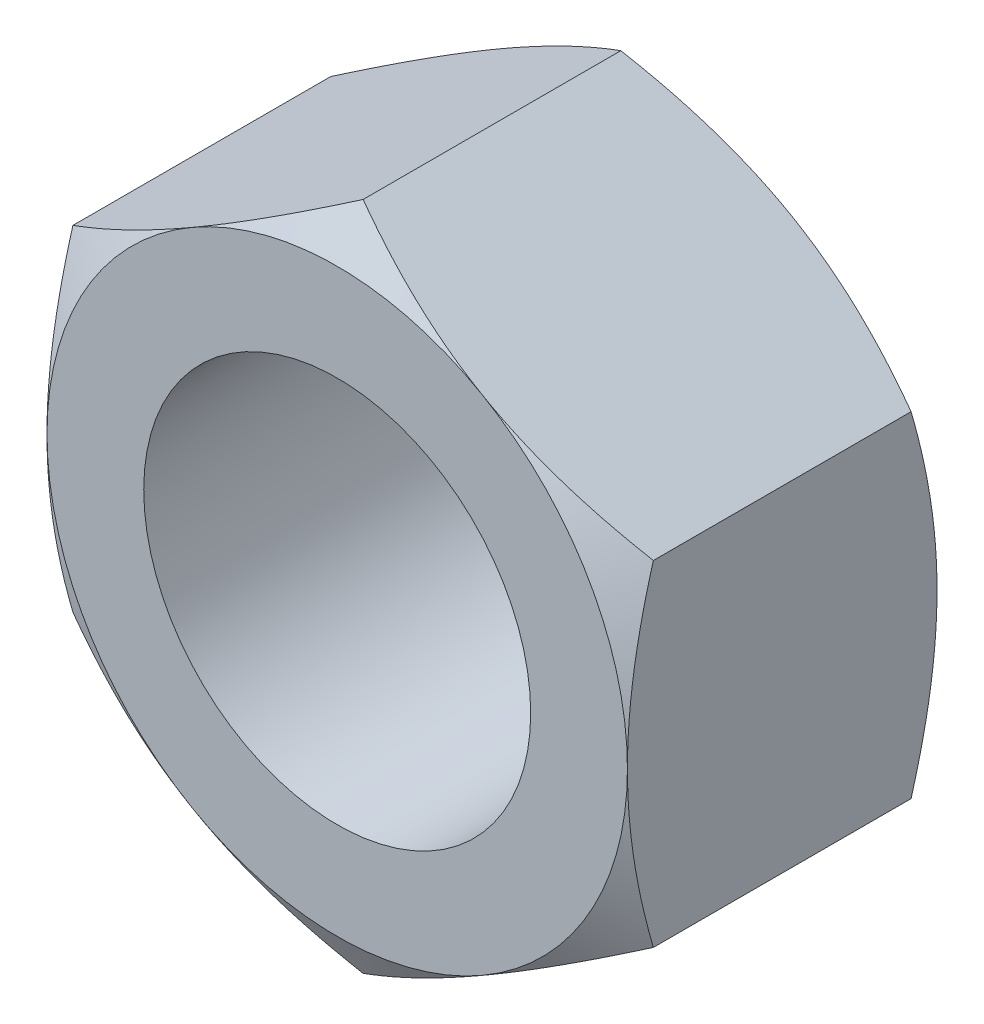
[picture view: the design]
ISO-10303-21;
HEADER;
FILE_DESCRIPTION(('STEP AP214'),'2;1');
FILE_NAME('part.step','',(''),(''),'','','');
FILE_SCHEMA(('AUTOMOTIVE_DESIGN { 1 0 10303 214 1 1 1 1 }'));
ENDSEC;
DATA;
#1=APPLICATION_CONTEXT('core data for automotive mechanical design processes');
#2=APPLICATION_PROTOCOL_DEFINITION('international standard','automotive_design',2000,#1);
#3=PRODUCT_CONTEXT('',#1,'mechanical');
#4=PRODUCT('Part','Part','',(#3));
#5=PRODUCT_RELATED_PRODUCT_CATEGORY('part','',(#4));
#6=PRODUCT_DEFINITION_FORMATION('','',#4);
#7=PRODUCT_DEFINITION_CONTEXT('part definition',#1,'design');
#8=PRODUCT_DEFINITION('design','',#6,#7);
#9=PRODUCT_DEFINITION_SHAPE('','',#8);
#10=(LENGTH_UNIT() NAMED_UNIT(*) SI_UNIT(.MILLI.,.METRE.));
#11=(NAMED_UNIT(*) PLANE_ANGLE_UNIT() SI_UNIT($,.RADIAN.));
#12=(NAMED_UNIT(*) SI_UNIT($,.STERADIAN.) SOLID_ANGLE_UNIT());
#13=UNCERTAINTY_MEASURE_WITH_UNIT(LENGTH_MEASURE(1.E-05),#10,'distance_accuracy_value','');
#14=(GEOMETRIC_REPRESENTATION_CONTEXT(3) GLOBAL_UNCERTAINTY_ASSIGNED_CONTEXT((#13)) GLOBAL_UNIT_ASSIGNED_CONTEXT((#10,
#11,#12)) REPRESENTATION_CONTEXT('',''));
#15=CARTESIAN_POINT('',(0.,0.,0.));
#16=DIRECTION('',(0.,0.,1.));
#17=DIRECTION('',(1.,0.,0.));
#18=AXIS2_PLACEMENT_3D('',#15,#16,#17);
#19=CARTESIAN_POINT('',(-15.,25.9807621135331,0.));
#20=DIRECTION('',(0.,0.,-1.));
#21=DIRECTION('',(-1.,0.,0.));
#22=AXIS2_PLACEMENT_3D('',#19,#20,#21);
#23=PLANE('',#22);
#24=CARTESIAN_POINT('',(0.,0.,0.));
#25=DIRECTION('',(0.,0.,1.));
#26=DIRECTION('',(1.,0.,0.));
#27=AXIS2_PLACEMENT_3D('',#24,#25,#26);
#28=CIRCLE('',#27,10.);
#29=CARTESIAN_POINT('',(10.,0.,0.));
#30=VERTEX_POINT('',#29);
#31=EDGE_CURVE('E319',#30,#30,#28,.T.);
#32=ORIENTED_EDGE('',*,*,#31,.F.);
#33=EDGE_LOOP('',(#32));
#34=FACE_BOUND('',#33,.T.);
#35=CARTESIAN_POINT('',(0.,0.,0.));
#36=DIRECTION('',(0.,0.,-1.));
#37=DIRECTION('',(-1.,0.,0.));
#38=AXIS2_PLACEMENT_3D('',#35,#36,#37);
#39=CIRCLE('',#38,15.);
#40=CARTESIAN_POINT('',(-14.9999999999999,0.,0.));
#41=VERTEX_POINT('',#40);
#42=CARTESIAN_POINT('',(-7.5000000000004,12.9903810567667,0.));
#43=VERTEX_POINT('',#42);
#44=EDGE_CURVE('E327',#41,#43,#39,.T.);
#45=ORIENTED_EDGE('',*,*,#44,.F.);
#46=CARTESIAN_POINT('',(0.,0.,0.));
#47=DIRECTION('',(0.,0.,-1.));
#48=DIRECTION('',(-1.,0.,0.));
#49=AXIS2_PLACEMENT_3D('',#46,#47,#48);
#50=CIRCLE('',#49,15.);
#51=CARTESIAN_POINT('',(-7.50000000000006,-12.9903810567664,0.));
#52=VERTEX_POINT('',#51);
#53=EDGE_CURVE('E149',#41,#52,#50,.F.);
#54=ORIENTED_EDGE('',*,*,#53,.T.);
#55=CARTESIAN_POINT('',(7.49999999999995,-12.9903810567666,0.));
#56=VERTEX_POINT('',#55);
#57=EDGE_CURVE('E251',#52,#56,#50,.F.);
#58=ORIENTED_EDGE('',*,*,#57,.T.);
#59=CARTESIAN_POINT('',(14.9999999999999,-2.22044604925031E-13,0.));
#60=VERTEX_POINT('',#59);
#61=EDGE_CURVE('E152',#56,#60,#50,.F.);
#62=ORIENTED_EDGE('',*,*,#61,.T.);
#63=CARTESIAN_POINT('',(7.50000000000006,12.9903810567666,0.));
#64=VERTEX_POINT('',#63);
#65=EDGE_CURVE('E127',#60,#64,#50,.F.);
#66=ORIENTED_EDGE('',*,*,#65,.T.);
#67=EDGE_CURVE('E140',#64,#43,#50,.F.);
#68=ORIENTED_EDGE('',*,*,#67,.T.);
#69=EDGE_LOOP('',(#45,#54,#58,#62,#66,#68));
#70=FACE_BOUND('',#69,.T.);
#71=ADVANCED_FACE('F32',(#34,#70),#23,.F.);
#72=CARTESIAN_POINT('',(0.,0.,0.));
#73=DIRECTION('',(0.,0.,-1.));
#74=DIRECTION('',(-1.,0.,0.));
#75=AXIS2_PLACEMENT_3D('',#72,#73,#74);
#76=CONICAL_SURFACE('',#75,15.,1.0471975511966);
#77=CARTESIAN_POINT('',(-15.0000000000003,-23.3393093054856,-7.35768755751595));
#78=CARTESIAN_POINT('',(-15.0000000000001,-23.0113763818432,-7.19841663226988));
#79=CARTESIAN_POINT('',(-15.0000000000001,-22.6830606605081,-7.03993424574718));
#80=CARTESIAN_POINT('',(-15.,-22.0255837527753,-6.724725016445));
#81=CARTESIAN_POINT('',(-15.,-21.6964225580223,-6.56799819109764));
#82=CARTESIAN_POINT('',(-15.0000000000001,-20.7074642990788,-6.10067791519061));
#83=CARTESIAN_POINT('',(-15.,-20.0462884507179,-5.79299136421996));
#84=CARTESIAN_POINT('',(-15.,-18.7159764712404,-5.18557696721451));
#85=CARTESIAN_POINT('',(-15.,-18.0468166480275,-4.88590088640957));
#86=CARTESIAN_POINT('',(-15.,-16.7032011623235,-4.29870839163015));
#87=CARTESIAN_POINT('',(-15.,-16.0287457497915,-4.01119140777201));
#88=CARTESIAN_POINT('',(-15.,-14.6515945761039,-3.44250105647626));
#89=CARTESIAN_POINT('',(-15.,-13.9486896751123,-3.16183152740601));
#90=CARTESIAN_POINT('',(-15.,-12.5346804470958,-2.62154818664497));
#91=CARTESIAN_POINT('',(-15.,-11.823575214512,-2.36193672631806));
#92=CARTESIAN_POINT('',(-15.,-10.3933623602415,-1.87053112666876));
#93=CARTESIAN_POINT('',(-15.,-9.67427399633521,-1.63868138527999));
#94=CARTESIAN_POINT('',(-15.,-8.22571576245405,-1.21017371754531));
#95=CARTESIAN_POINT('',(-15.,-7.4962492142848,-1.01350479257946));
#96=CARTESIAN_POINT('',(-15.,-6.39610270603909,-0.752490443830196));
#97=CARTESIAN_POINT('',(-15.,-6.02939002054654,-0.671323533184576));
#98=CARTESIAN_POINT('',(-15.,-5.29344467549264,-0.521286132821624));
#99=CARTESIAN_POINT('',(-15.,-4.92421206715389,-0.452415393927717));
#100=CARTESIAN_POINT('',(-15.,-4.18347621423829,-0.328181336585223));
#101=CARTESIAN_POINT('',(-15.,-3.81197300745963,-0.272817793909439));
#102=CARTESIAN_POINT('',(-15.,-3.06708460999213,-0.176699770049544));
#103=CARTESIAN_POINT('',(-15.,-2.69369950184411,-0.135944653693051));
#104=CARTESIAN_POINT('',(-15.,-1.95047864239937,-0.0703683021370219));
#105=CARTESIAN_POINT('',(-15.,-1.58066088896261,-0.0453443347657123));
#106=CARTESIAN_POINT('',(-15.,-0.840299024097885,-0.0109620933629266));
#107=CARTESIAN_POINT('',(-15.0000000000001,-0.469754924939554,-0.00160355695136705));
#108=CARTESIAN_POINT('',(-15.,0.271400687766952,0.0012249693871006));
#109=CARTESIAN_POINT('',(-15.,0.642012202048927,-0.00530522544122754));
#110=CARTESIAN_POINT('',(-15.0000000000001,1.38262798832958,-0.0340942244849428));
#111=CARTESIAN_POINT('',(-15.0000000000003,1.75263223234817,-0.0563537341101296));
#112=CARTESIAN_POINT('',(-15.0000000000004,2.63937167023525,-0.128074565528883));
#113=CARTESIAN_POINT('',(-15.0000000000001,3.15552506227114,-0.18485970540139));
#114=CARTESIAN_POINT('',(-14.9999999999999,4.18405620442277,-0.325966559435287));
#115=CARTESIAN_POINT('',(-15.,4.69643344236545,-0.41029194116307));
#116=CARTESIAN_POINT('',(-15.0000000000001,5.71689756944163,-0.603479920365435));
#117=CARTESIAN_POINT('',(-15.,6.22498092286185,-0.712361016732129));
#118=CARTESIAN_POINT('',(-15.,7.23607939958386,-0.951336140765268));
#119=CARTESIAN_POINT('',(-15.,7.73909459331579,-1.08142987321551));
#120=CARTESIAN_POINT('',(-15.,8.75152378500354,-1.36284884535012));
#121=CARTESIAN_POINT('',(-15.,9.26082088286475,-1.51459173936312));
#122=CARTESIAN_POINT('',(-15.,10.27439709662,-1.83391678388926));
#123=CARTESIAN_POINT('',(-15.,10.7786761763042,-2.00149904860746));
#124=CARTESIAN_POINT('',(-15.,11.7824677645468,-2.34982725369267));
#125=CARTESIAN_POINT('',(-15.,12.2819817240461,-2.53056903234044));
#126=CARTESIAN_POINT('',(-15.,13.276854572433,-2.90307352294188));
#127=CARTESIAN_POINT('',(-15.,13.7722135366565,-3.09483603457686));
#128=CARTESIAN_POINT('',(-15.,15.0436675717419,-3.60070607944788));
#129=CARTESIAN_POINT('',(-15.,15.817045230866,-3.92163726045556));
#130=CARTESIAN_POINT('',(-15.,17.3564052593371,-4.5808277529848));
#131=CARTESIAN_POINT('',(-15.,18.1223869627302,-4.91908860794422));
#132=CARTESIAN_POINT('',(-15.,19.6485392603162,-5.60905898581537));
#133=CARTESIAN_POINT('',(-15.,20.4087079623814,-5.9607726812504));
#134=CARTESIAN_POINT('',(-15.,21.9240967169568,-6.67461099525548));
#135=CARTESIAN_POINT('',(-15.,22.6793169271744,-7.03673528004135));
#136=CARTESIAN_POINT('',(-15.,24.1867764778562,-7.76974794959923));
#137=CARTESIAN_POINT('',(-15.,24.9390102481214,-8.14064776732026));
#138=CARTESIAN_POINT('',(-15.,26.4401635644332,-8.88909646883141));
#139=CARTESIAN_POINT('',(-15.,27.1890830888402,-9.26664539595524));
#140=CARTESIAN_POINT('',(-15.,28.6840389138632,-10.027077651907));
#141=CARTESIAN_POINT('',(-15.,29.4300757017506,-10.4099600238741));
#142=CARTESIAN_POINT('',(-15.,30.9198465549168,-11.1801693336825));
#143=CARTESIAN_POINT('',(-15.,31.6635806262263,-11.5674962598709));
#144=CARTESIAN_POINT('',(-15.,33.7472761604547,-12.6592216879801));
#145=CARTESIAN_POINT('',(-15.,35.0850614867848,-13.3677730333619));
#146=CARTESIAN_POINT('',(-15.,37.756014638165,-14.7936653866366));
#147=CARTESIAN_POINT('',(-15.,39.0891822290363,-15.5110068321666));
#148=CARTESIAN_POINT('',(-15.,41.7479806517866,-16.9501647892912));
#149=CARTESIAN_POINT('',(-15.,43.0736221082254,-17.6719616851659));
#150=CARTESIAN_POINT('',(-15.,45.0599534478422,-18.7584424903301));
#151=CARTESIAN_POINT('',(-15.,45.7216867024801,-19.1212214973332));
#152=CARTESIAN_POINT('',(-15.,47.0445303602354,-19.8479113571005));
#153=CARTESIAN_POINT('',(-15.0000000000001,47.7056407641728,-20.211822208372));
#154=CARTESIAN_POINT('',(-15.0000000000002,48.366476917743,-20.5762305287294));
#155=B_SPLINE_CURVE_WITH_KNOTS('',3,(#77,#78,#79,#80,#81,#82,#83,#84,#85,#86,#87,#88,#89,#90,
#91,#92,#93,#94,#95,#96,#97,#98,#99,#100,#101,#102,#103,#104,#105,#106,#107,#108,#109,#110,#111,
#112,#113,#114,#115,#116,#117,#118,#119,#120,#121,#122,#123,#124,#125,#126,#127,#128,#129,#130,
#131,#132,#133,#134,#135,#136,#137,#138,#139,#140,#141,#142,#143,#144,#145,#146,#147,#148,#149,
#150,#151,#152,#153,#154),.UNSPECIFIED.,.F.,.F.,(4,2,2,2,2,2,2,2,2,2,2,2,2,2,2,2,2,2,2,2,2,2,2,
2,2,2,2,2,2,2,2,2,2,2,2,2,2,2,4),(0.,1.09369135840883,2.1873935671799,4.37511793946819,
6.57462034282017,8.77401954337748,11.0443689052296,13.3149714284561,15.5809474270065,
17.8462137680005,18.9728046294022,20.099372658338,21.2259219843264,22.3524223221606,
23.4640902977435,24.5757396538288,25.6874019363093,26.799114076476,28.3560578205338,
29.9132089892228,31.4715371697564,33.0298436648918,34.6238022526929,36.2177723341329,
37.8112404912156,39.4046796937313,41.9163419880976,44.4282283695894,46.9409002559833,
49.4534916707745,51.9695595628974,54.4856438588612,57.0012824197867,59.5169143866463,
64.0583868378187,68.6000863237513,73.1282984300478,75.3922533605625,77.6562053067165),.UNSPECIFIED.);
#156=CARTESIAN_POINT('',(-15.,8.66025403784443,-1.33974596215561));
#157=VERTEX_POINT('',#156);
#158=EDGE_CURVE('E157',#157,#41,#155,.F.);
#159=ORIENTED_EDGE('',*,*,#158,.T.);
#160=ORIENTED_EDGE('',*,*,#44,.T.);
#161=CARTESIAN_POINT('',(0.000200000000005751,17.3206235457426,-1.3398126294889));
#162=CARTESIAN_POINT('',(-0.329494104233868,17.1302745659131,-1.22992178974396));
#163=CARTESIAN_POINT('',(-0.660474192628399,16.9391831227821,-1.12501758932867));
#164=CARTESIAN_POINT('',(-1.32508844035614,16.5554679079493,-0.92656858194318));
#165=CARTESIAN_POINT('',(-1.65872343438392,16.3628436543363,-0.833027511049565));
#166=CARTESIAN_POINT('',(-2.32929228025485,15.9756905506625,-0.658562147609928));
#167=CARTESIAN_POINT('',(-2.66623200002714,15.7811583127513,-0.577667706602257));
#168=CARTESIAN_POINT('',(-3.34245276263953,15.3907420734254,-0.430232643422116));
#169=CARTESIAN_POINT('',(-3.68173367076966,15.1948581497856,-0.363691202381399));
#170=CARTESIAN_POINT('',(-4.35394314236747,14.8067578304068,-0.247792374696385));
#171=CARTESIAN_POINT('',(-4.6868218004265,14.6145702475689,-0.198051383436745));
#172=CARTESIAN_POINT('',(-5.35410443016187,14.2293144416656,-0.114646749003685));
#173=CARTESIAN_POINT('',(-5.68850843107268,14.0362462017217,-0.0809834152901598));
#174=CARTESIAN_POINT('',(-6.35787818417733,13.6497853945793,-0.0305840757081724));
#175=CARTESIAN_POINT('',(-6.6928427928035,13.4563934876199,-0.013827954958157));
#176=CARTESIAN_POINT('',(-7.36308121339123,13.0694311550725,0.0023966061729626));
#177=CARTESIAN_POINT('',(-7.69835501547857,12.8758607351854,0.00186558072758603));
#178=CARTESIAN_POINT('',(-8.32514688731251,12.5139822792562,-0.0152766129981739));
#179=CARTESIAN_POINT('',(-8.61670962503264,12.3456484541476,-0.0297968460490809));
#180=CARTESIAN_POINT('',(-9.19916443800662,12.0093680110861,-0.0716371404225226));
#181=CARTESIAN_POINT('',(-9.49005646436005,11.8414214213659,-0.0989581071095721));
#182=CARTESIAN_POINT('',(-10.0710118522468,11.5060066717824,-0.165923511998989));
#183=CARTESIAN_POINT('',(-10.3610743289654,11.3385390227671,-0.20557812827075));
#184=CARTESIAN_POINT('',(-10.9398394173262,11.0043888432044,-0.296515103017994));
#185=CARTESIAN_POINT('',(-11.2285419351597,10.8377063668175,-0.347798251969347));
#186=CARTESIAN_POINT('',(-12.1049144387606,10.3317324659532,-0.520386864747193));
#187=CARTESIAN_POINT('',(-12.6900465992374,9.99390625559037,-0.658901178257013));
#188=CARTESIAN_POINT('',(-13.8515859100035,9.32329122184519,-0.973271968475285));
#189=CARTESIAN_POINT('',(-14.4280079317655,8.99049381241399,-1.14905461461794));
#190=CARTESIAN_POINT('',(-15.0002,8.66013856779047,-1.33981262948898));
#191=B_SPLINE_CURVE_WITH_KNOTS('',3,(#161,#162,#163,#164,#165,#166,#167,#168,#169,#170,#171,
#172,#173,#174,#175,#176,#177,#178,#179,#180,#181,#182,#183,#184,#185,#186,#187,#188,#189,#190),
.UNSPECIFIED.,.F.,.F.,(4,2,2,2,2,2,2,2,2,2,2,2,2,2,4),(0.,1.18875411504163,2.37789802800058,
3.56980778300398,4.76164951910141,5.92407379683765,7.0865204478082,8.24758247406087,
9.40860862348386,10.4193068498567,11.4300765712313,12.4416826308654,13.4533574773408,
15.5211962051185,17.5849760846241),.UNSPECIFIED.);
#192=EDGE_CURVE('E189',#43,#157,#191,.T.);
#193=ORIENTED_EDGE('',*,*,#192,.T.);
#194=EDGE_LOOP('',(#159,#160,#193));
#195=FACE_BOUND('',#194,.T.);
#196=ADVANCED_FACE('F176',(#195),#76,.T.);
#197=CARTESIAN_POINT('',(15.0001999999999,8.66013856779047,-1.3398126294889));
#198=CARTESIAN_POINT('',(14.6705058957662,8.85048754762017,-1.22992178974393));
#199=CARTESIAN_POINT('',(14.3395258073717,9.04157899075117,-1.12501758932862));
#200=CARTESIAN_POINT('',(13.674911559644,9.42529420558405,-0.926568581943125));
#201=CARTESIAN_POINT('',(13.3412765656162,9.61791845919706,-0.833027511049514));
#202=CARTESIAN_POINT('',(12.6707077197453,10.0050715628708,-0.658562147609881));
#203=CARTESIAN_POINT('',(12.333767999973,10.199603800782,-0.577667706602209));
#204=CARTESIAN_POINT('',(11.6575472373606,10.5900200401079,-0.430232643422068));
#205=CARTESIAN_POINT('',(11.3182663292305,10.7859039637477,-0.363691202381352));
#206=CARTESIAN_POINT('',(10.6460568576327,11.1740042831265,-0.247792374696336));
#207=CARTESIAN_POINT('',(10.3131781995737,11.3661918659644,-0.198051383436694));
#208=CARTESIAN_POINT('',(9.6458955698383,11.7514476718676,-0.114646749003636));
#209=CARTESIAN_POINT('',(9.3114915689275,11.9445159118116,-0.0809834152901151));
#210=CARTESIAN_POINT('',(8.64212181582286,12.3309767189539,-0.0305840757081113));
#211=CARTESIAN_POINT('',(8.30715720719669,12.5243686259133,-0.0138279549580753));
#212=CARTESIAN_POINT('',(7.63691878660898,12.9113309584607,0.0023966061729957));
#213=CARTESIAN_POINT('',(7.30164498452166,13.1049013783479,0.00186558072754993));
#214=CARTESIAN_POINT('',(6.67485311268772,13.4667798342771,-0.0152766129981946));
#215=CARTESIAN_POINT('',(6.38329037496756,13.6351136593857,-0.0297968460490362));
#216=CARTESIAN_POINT('',(5.80083556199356,13.9713941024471,-0.0716371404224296));
#217=CARTESIAN_POINT('',(5.50994353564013,14.1393406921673,-0.0989581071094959));
#218=CARTESIAN_POINT('',(4.92898814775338,14.4747554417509,-0.165923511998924));
#219=CARTESIAN_POINT('',(4.63892567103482,14.6422230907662,-0.20557812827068));
#220=CARTESIAN_POINT('',(4.06016058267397,14.9763732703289,-0.296515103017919));
#221=CARTESIAN_POINT('',(3.77145806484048,15.1430557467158,-0.347798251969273));
#222=CARTESIAN_POINT('',(2.89508556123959,15.6490296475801,-0.52038686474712));
#223=CARTESIAN_POINT('',(2.30995340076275,15.9868558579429,-0.658901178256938));
#224=CARTESIAN_POINT('',(1.14841408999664,16.6574708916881,-0.973271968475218));
#225=CARTESIAN_POINT('',(0.571992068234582,16.9902683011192,-1.14905461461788));
#226=CARTESIAN_POINT('',(-0.000200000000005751,17.3206235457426,-1.33981262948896));
#227=B_SPLINE_CURVE_WITH_KNOTS('',3,(#197,#198,#199,#200,#201,#202,#203,#204,#205,#206,#207,
#208,#209,#210,#211,#212,#213,#214,#215,#216,#217,#218,#219,#220,#221,#222,#223,#224,#225,#226),
.UNSPECIFIED.,.F.,.F.,(4,2,2,2,2,2,2,2,2,2,2,2,2,2,4),(0.,1.18875411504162,2.37789802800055,
3.56980778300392,4.76164951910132,5.92407379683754,7.08652044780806,8.24758247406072,
9.4086086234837,10.4193068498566,11.4300765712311,12.4416826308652,13.4533574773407,
15.5211962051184,17.584976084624),.UNSPECIFIED.);
#228=CARTESIAN_POINT('',(-1.11022302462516E-13,17.3205080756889,-1.33974596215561));
#229=VERTEX_POINT('',#228);
#230=EDGE_CURVE('E136',#64,#229,#227,.T.);
#231=ORIENTED_EDGE('',*,*,#230,.T.);
#232=EDGE_CURVE('E143',#229,#43,#191,.T.);
#233=ORIENTED_EDGE('',*,*,#232,.T.);
#234=ORIENTED_EDGE('',*,*,#67,.F.);
#235=EDGE_LOOP('',(#231,#233,#234));
#236=FACE_BOUND('',#235,.T.);
#237=ADVANCED_FACE('F141',(#236),#76,.T.);
#238=CARTESIAN_POINT('',(15.,-23.3393093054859,-7.35768755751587));
#239=CARTESIAN_POINT('',(14.9999999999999,-23.0113763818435,-7.19841663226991));
#240=CARTESIAN_POINT('',(14.9999999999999,-22.6830606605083,-7.03993424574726));
#241=CARTESIAN_POINT('',(14.9999999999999,-22.0255837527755,-6.72472501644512));
#242=CARTESIAN_POINT('',(14.9999999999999,-21.6964225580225,-6.56799819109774));
#243=CARTESIAN_POINT('',(14.9999999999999,-20.707464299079,-6.10067791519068));
#244=CARTESIAN_POINT('',(14.9999999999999,-20.0462884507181,-5.79299136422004));
#245=CARTESIAN_POINT('',(14.9999999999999,-18.7159764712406,-5.18557696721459));
#246=CARTESIAN_POINT('',(14.9999999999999,-18.0468166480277,-4.88590088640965));
#247=CARTESIAN_POINT('',(14.9999999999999,-16.7032011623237,-4.29870839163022));
#248=CARTESIAN_POINT('',(14.9999999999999,-16.0287457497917,-4.01119140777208));
#249=CARTESIAN_POINT('',(14.9999999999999,-14.6515945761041,-3.44250105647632));
#250=CARTESIAN_POINT('',(14.9999999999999,-13.9486896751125,-3.16183152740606));
#251=CARTESIAN_POINT('',(14.9999999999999,-12.534680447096,-2.62154818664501));
#252=CARTESIAN_POINT('',(14.9999999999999,-11.8235752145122,-2.3619367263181));
#253=CARTESIAN_POINT('',(14.9999999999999,-10.3933623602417,-1.8705311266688));
#254=CARTESIAN_POINT('',(14.9999999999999,-9.6742739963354,-1.63868138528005));
#255=CARTESIAN_POINT('',(14.9999999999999,-8.22571576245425,-1.21017371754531));
#256=CARTESIAN_POINT('',(14.9999999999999,-7.49624921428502,-1.01350479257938));
#257=CARTESIAN_POINT('',(14.9999999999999,-6.3961027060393,-0.75249044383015));
#258=CARTESIAN_POINT('',(14.9999999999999,-6.02939002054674,-0.671323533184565));
#259=CARTESIAN_POINT('',(14.9999999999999,-5.29344467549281,-0.521286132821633));
#260=CARTESIAN_POINT('',(14.9999999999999,-4.92421206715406,-0.452415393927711));
#261=CARTESIAN_POINT('',(14.9999999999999,-4.18347621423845,-0.328181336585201));
#262=CARTESIAN_POINT('',(14.9999999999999,-3.81197300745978,-0.272817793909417));
#263=CARTESIAN_POINT('',(14.9999999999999,-3.06708460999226,-0.176699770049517));
#264=CARTESIAN_POINT('',(14.9999999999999,-2.69369950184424,-0.135944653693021));
#265=CARTESIAN_POINT('',(14.9999999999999,-1.95047864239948,-0.0703683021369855));
#266=CARTESIAN_POINT('',(14.9999999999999,-1.58066088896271,-0.0453443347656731));
#267=CARTESIAN_POINT('',(14.9999999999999,-0.840299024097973,-0.0109620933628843));
#268=CARTESIAN_POINT('',(14.9999999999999,-0.469754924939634,-0.0016035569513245));
#269=CARTESIAN_POINT('',(14.9999999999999,0.271400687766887,0.00122496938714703));
#270=CARTESIAN_POINT('',(14.9999999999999,0.642012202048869,-0.0053052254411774));
#271=CARTESIAN_POINT('',(14.9999999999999,1.38262798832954,-0.0340942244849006));
#272=CARTESIAN_POINT('',(14.9999999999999,1.75263223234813,-0.0563537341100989));
#273=CARTESIAN_POINT('',(14.9999999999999,2.63937167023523,-0.128074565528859));
#274=CARTESIAN_POINT('',(14.9999999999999,3.15552506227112,-0.184859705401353));
#275=CARTESIAN_POINT('',(14.9999999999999,4.18405620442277,-0.325966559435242));
#276=CARTESIAN_POINT('',(14.9999999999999,4.69643344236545,-0.41029194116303));
#277=CARTESIAN_POINT('',(14.9999999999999,5.71689756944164,-0.603479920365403));
#278=CARTESIAN_POINT('',(14.9999999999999,6.22498092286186,-0.712361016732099));
#279=CARTESIAN_POINT('',(14.9999999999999,7.23607939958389,-0.951336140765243));
#280=CARTESIAN_POINT('',(14.9999999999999,7.73909459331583,-1.08142987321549));
#281=CARTESIAN_POINT('',(14.9999999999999,8.75152378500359,-1.36284884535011));
#282=CARTESIAN_POINT('',(14.9999999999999,9.26082088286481,-1.51459173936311));
#283=CARTESIAN_POINT('',(14.9999999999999,10.2743970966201,-1.83391678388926));
#284=CARTESIAN_POINT('',(14.9999999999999,10.7786761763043,-2.00149904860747));
#285=CARTESIAN_POINT('',(14.9999999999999,11.7824677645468,-2.34982725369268));
#286=CARTESIAN_POINT('',(14.9999999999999,12.2819817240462,-2.53056903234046));
#287=CARTESIAN_POINT('',(14.9999999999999,13.2768545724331,-2.90307352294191));
#288=CARTESIAN_POINT('',(14.9999999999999,13.7722135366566,-3.09483603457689));
#289=CARTESIAN_POINT('',(14.9999999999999,15.043667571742,-3.60070607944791));
#290=CARTESIAN_POINT('',(14.9999999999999,15.8170452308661,-3.92163726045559));
#291=CARTESIAN_POINT('',(14.9999999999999,17.3564052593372,-4.58082775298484));
#292=CARTESIAN_POINT('',(14.9999999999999,18.1223869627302,-4.91908860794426));
#293=CARTESIAN_POINT('',(14.9999999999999,19.6485392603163,-5.60905898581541));
#294=CARTESIAN_POINT('',(14.9999999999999,20.4087079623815,-5.96077268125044));
#295=CARTESIAN_POINT('',(14.9999999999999,21.9240967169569,-6.67461099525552));
#296=CARTESIAN_POINT('',(14.9999999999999,22.6793169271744,-7.03673528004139));
#297=CARTESIAN_POINT('',(14.9999999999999,24.1867764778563,-7.76974794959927));
#298=CARTESIAN_POINT('',(14.9999999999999,24.9390102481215,-8.1406477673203));
#299=CARTESIAN_POINT('',(14.9999999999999,26.4401635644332,-8.88909646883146));
#300=CARTESIAN_POINT('',(14.9999999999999,27.1890830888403,-9.26664539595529));
#301=CARTESIAN_POINT('',(14.9999999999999,28.6840389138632,-10.0270776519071));
#302=CARTESIAN_POINT('',(14.9999999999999,29.4300757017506,-10.4099600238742));
#303=CARTESIAN_POINT('',(14.9999999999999,30.9198465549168,-11.1801693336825));
#304=CARTESIAN_POINT('',(14.9999999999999,31.6635806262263,-11.5674962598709));
#305=CARTESIAN_POINT('',(14.9999999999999,33.7472761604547,-12.6592216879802));
#306=CARTESIAN_POINT('',(14.9999999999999,35.0850614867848,-13.367773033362));
#307=CARTESIAN_POINT('',(14.9999999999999,37.7560146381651,-14.7936653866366));
#308=CARTESIAN_POINT('',(14.9999999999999,39.0891822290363,-15.5110068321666));
#309=CARTESIAN_POINT('',(14.9999999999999,41.7479806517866,-16.9501647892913));
#310=CARTESIAN_POINT('',(14.9999999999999,43.0736221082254,-17.6719616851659));
#311=CARTESIAN_POINT('',(14.9999999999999,45.0599534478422,-18.7584424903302));
#312=CARTESIAN_POINT('',(14.9999999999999,45.7216867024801,-19.1212214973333));
#313=CARTESIAN_POINT('',(14.9999999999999,47.0445303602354,-19.8479113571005));
#314=CARTESIAN_POINT('',(15.,47.7056407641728,-20.211822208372));
#315=CARTESIAN_POINT('',(15.,48.3664769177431,-20.5762305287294));
#316=B_SPLINE_CURVE_WITH_KNOTS('',3,(#238,#239,#240,#241,#242,#243,#244,#245,#246,#247,#248,
#249,#250,#251,#252,#253,#254,#255,#256,#257,#258,#259,#260,#261,#262,#263,#264,#265,#266,#267,
#268,#269,#270,#271,#272,#273,#274,#275,#276,#277,#278,#279,#280,#281,#282,#283,#284,#285,#286,
#287,#288,#289,#290,#291,#292,#293,#294,#295,#296,#297,#298,#299,#300,#301,#302,#303,#304,#305,
#306,#307,#308,#309,#310,#311,#312,#313,#314,#315),.UNSPECIFIED.,.F.,.F.,(4,2,2,2,2,2,2,2,2,2,2,
2,2,2,2,2,2,2,2,2,2,2,2,2,2,2,2,2,2,2,2,2,2,2,2,2,2,2,4),(0.,1.09369135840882,2.18739356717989,
4.37511793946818,6.57462034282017,8.7740195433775,11.0443689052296,13.3149714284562,
15.5809474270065,17.8462137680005,18.9728046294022,20.099372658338,21.2259219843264,
22.3524223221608,23.4640902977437,24.5757396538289,25.6874019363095,26.7991140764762,
28.356057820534,29.913208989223,31.4715371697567,33.0298436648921,34.6238022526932,
36.2177723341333,37.8112404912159,39.4046796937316,41.9163419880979,44.4282283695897,
46.9409002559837,49.4534916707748,51.9695595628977,54.4856438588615,57.001282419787,
59.5169143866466,64.058386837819,68.6000863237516,73.1282984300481,75.3922533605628,
77.6562053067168),.UNSPECIFIED.);
#317=CARTESIAN_POINT('',(15.0000000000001,8.66025403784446,-1.33974596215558));
#318=VERTEX_POINT('',#317);
#319=EDGE_CURVE('E130',#60,#318,#316,.T.);
#320=ORIENTED_EDGE('',*,*,#319,.T.);
#321=EDGE_CURVE('E123',#318,#64,#227,.T.);
#322=ORIENTED_EDGE('',*,*,#321,.T.);
#323=ORIENTED_EDGE('',*,*,#65,.F.);
#324=EDGE_LOOP('',(#320,#322,#323));
#325=FACE_BOUND('',#324,.T.);
#326=ADVANCED_FACE('F125',(#325),#76,.T.);
#327=CARTESIAN_POINT('',(-0.000199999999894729,-17.3206235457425,-1.33981262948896));
#328=CARTESIAN_POINT('',(0.329494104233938,-17.130274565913,-1.22992178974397));
#329=CARTESIAN_POINT('',(0.660474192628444,-16.9391831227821,-1.12501758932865));
#330=CARTESIAN_POINT('',(1.32508844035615,-16.5554679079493,-0.92656858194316));
#331=CARTESIAN_POINT('',(1.65872343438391,-16.3628436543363,-0.833027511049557));
#332=CARTESIAN_POINT('',(2.3292922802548,-15.9756905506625,-0.658562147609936));
#333=CARTESIAN_POINT('',(2.66623200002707,-15.7811583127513,-0.577667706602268));
#334=CARTESIAN_POINT('',(3.34245276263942,-15.3907420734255,-0.430232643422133));
#335=CARTESIAN_POINT('',(3.68173367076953,-15.1948581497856,-0.36369120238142));
#336=CARTESIAN_POINT('',(4.3539431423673,-14.8067578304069,-0.24779237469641));
#337=CARTESIAN_POINT('',(4.68682180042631,-14.614570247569,-0.19805138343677));
#338=CARTESIAN_POINT('',(5.35410443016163,-14.2293144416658,-0.11464674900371));
#339=CARTESIAN_POINT('',(5.68850843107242,-14.0362462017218,-0.0809834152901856));
#340=CARTESIAN_POINT('',(6.35787818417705,-13.6497853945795,-0.0305840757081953));
#341=CARTESIAN_POINT('',(6.69284279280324,-13.4563934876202,-0.0138279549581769));
#342=CARTESIAN_POINT('',(7.36308121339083,-13.0694311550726,0.00239660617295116));
#343=CARTESIAN_POINT('',(7.69835501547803,-12.8758607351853,0.00186558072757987));
#344=CARTESIAN_POINT('',(8.32514688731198,-12.5139822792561,-0.0152766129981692));
#345=CARTESIAN_POINT('',(8.61670962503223,-12.3456484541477,-0.029796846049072));
#346=CARTESIAN_POINT('',(9.19916443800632,-12.0093680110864,-0.0716371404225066));
#347=CARTESIAN_POINT('',(9.49005646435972,-11.8414214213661,-0.098958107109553));
#348=CARTESIAN_POINT('',(10.0710118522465,-11.5060066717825,-0.165923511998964));
#349=CARTESIAN_POINT('',(10.361074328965,-11.3385390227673,-0.205578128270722));
#350=CARTESIAN_POINT('',(10.9398394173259,-11.0043888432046,-0.296515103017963));
#351=CARTESIAN_POINT('',(11.2285419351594,-10.8377063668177,-0.347798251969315));
#352=CARTESIAN_POINT('',(12.1049144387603,-10.3317324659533,-0.520386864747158));
#353=CARTESIAN_POINT('',(12.6900465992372,-9.99390625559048,-0.658901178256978));
#354=CARTESIAN_POINT('',(13.8515859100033,-9.3232912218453,-0.973271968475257));
#355=CARTESIAN_POINT('',(14.4280079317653,-8.99049381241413,-1.14905461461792));
#356=CARTESIAN_POINT('',(15.0001999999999,-8.66013856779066,-1.33981262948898));
#357=B_SPLINE_CURVE_WITH_KNOTS('',3,(#327,#328,#329,#330,#331,#332,#333,#334,#335,#336,#337,
#338,#339,#340,#341,#342,#343,#344,#345,#346,#347,#348,#349,#350,#351,#352,#353,#354,#355,#356),
.UNSPECIFIED.,.F.,.F.,(4,2,2,2,2,2,2,2,2,2,2,2,2,2,4),(0.,1.18875411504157,2.37789802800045,
3.56980778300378,4.76164951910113,5.92407379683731,7.08652044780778,8.24758247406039,
9.40860862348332,10.4193068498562,11.4300765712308,12.4416826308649,13.4533574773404,
15.5211962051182,17.5849760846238),.UNSPECIFIED.);
#358=CARTESIAN_POINT('',(14.9999999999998,-8.66025403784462,-1.33974596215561));
#359=VERTEX_POINT('',#358);
#360=EDGE_CURVE('E203',#56,#359,#357,.T.);
#361=ORIENTED_EDGE('',*,*,#360,.T.);
#362=EDGE_CURVE('E202',#359,#60,#316,.T.);
#363=ORIENTED_EDGE('',*,*,#362,.T.);
#364=ORIENTED_EDGE('',*,*,#61,.F.);
#365=EDGE_LOOP('',(#361,#363,#364));
#366=FACE_BOUND('',#365,.T.);
#367=ADVANCED_FACE('F386',(#366),#76,.T.);
#368=CARTESIAN_POINT('',(0.,-17.3205080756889,-1.33974596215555));
#369=VERTEX_POINT('',#368);
#370=EDGE_CURVE('E261',#369,#56,#357,.T.);
#371=ORIENTED_EDGE('',*,*,#370,.T.);
#372=ORIENTED_EDGE('',*,*,#57,.F.);
#373=CARTESIAN_POINT('',(-15.0002000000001,-8.66013856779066,-1.33981262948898));
#374=CARTESIAN_POINT('',(-14.6705058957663,-8.85048754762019,-1.22992178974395));
#375=CARTESIAN_POINT('',(-14.3395258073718,-9.04157899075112,-1.12501758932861));
#376=CARTESIAN_POINT('',(-13.674911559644,-9.42529420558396,-0.926568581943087));
#377=CARTESIAN_POINT('',(-13.3412765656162,-9.61791845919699,-0.83302751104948));
#378=CARTESIAN_POINT('',(-12.6707077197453,-10.0050715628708,-0.65856214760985));
#379=CARTESIAN_POINT('',(-12.333767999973,-10.199603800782,-0.577667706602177));
#380=CARTESIAN_POINT('',(-11.6575472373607,-10.5900200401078,-0.430232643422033));
#381=CARTESIAN_POINT('',(-11.3182663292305,-10.7859039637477,-0.363691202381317));
#382=CARTESIAN_POINT('',(-10.6460568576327,-11.1740042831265,-0.247792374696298));
#383=CARTESIAN_POINT('',(-10.3131781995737,-11.3661918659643,-0.198051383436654));
#384=CARTESIAN_POINT('',(-9.64589556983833,-11.7514476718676,-0.114646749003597));
#385=CARTESIAN_POINT('',(-9.31149156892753,-11.9445159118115,-0.0809834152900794));
#386=CARTESIAN_POINT('',(-8.64212181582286,-12.3309767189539,-0.0305840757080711));
#387=CARTESIAN_POINT('',(-8.30715720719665,-12.5243686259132,-0.013827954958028));
#388=CARTESIAN_POINT('',(-7.63691878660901,-12.9113309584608,0.00239660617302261));
#389=CARTESIAN_POINT('',(-7.30164498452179,-13.1049013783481,0.00186558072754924));
#390=CARTESIAN_POINT('',(-6.67485311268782,-13.4667798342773,-0.0152766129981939));
#391=CARTESIAN_POINT('',(-6.38329037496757,-13.6351136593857,-0.0297968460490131));
#392=CARTESIAN_POINT('',(-5.8008355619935,-13.9713941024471,-0.0716371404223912));
#393=CARTESIAN_POINT('',(-5.50994353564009,-14.1393406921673,-0.0989581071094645));
#394=CARTESIAN_POINT('',(-4.92898814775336,-14.4747554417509,-0.1659235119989));
#395=CARTESIAN_POINT('',(-4.6389256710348,-14.6422230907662,-0.205578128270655));
#396=CARTESIAN_POINT('',(-4.06016058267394,-14.9763732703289,-0.296515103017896));
#397=CARTESIAN_POINT('',(-3.77145806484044,-15.1430557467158,-0.347798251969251));
#398=CARTESIAN_POINT('',(-2.89508556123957,-15.6490296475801,-0.520386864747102));
#399=CARTESIAN_POINT('',(-2.30995340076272,-15.9868558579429,-0.658901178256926));
#400=CARTESIAN_POINT('',(-1.14841408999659,-16.6574708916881,-0.973271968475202));
#401=CARTESIAN_POINT('',(-0.571992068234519,-16.9902683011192,-1.14905461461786));
#402=CARTESIAN_POINT('',(0.000200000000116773,-17.3206235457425,-1.3398126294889));
#403=B_SPLINE_CURVE_WITH_KNOTS('',3,(#373,#374,#375,#376,#377,#378,#379,#380,#381,#382,#383,
#384,#385,#386,#387,#388,#389,#390,#391,#392,#393,#394,#395,#396,#397,#398,#399,#400,#401,#402),
.UNSPECIFIED.,.F.,.F.,(4,2,2,2,2,2,2,2,2,2,2,2,2,2,4),(0.,1.18875411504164,2.37789802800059,
3.56980778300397,4.76164951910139,5.92407379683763,7.08652044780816,8.24758247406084,
9.40860862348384,10.4193068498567,11.4300765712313,12.4416826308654,13.4533574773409,
15.5211962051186,17.5849760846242),.UNSPECIFIED.);
#404=EDGE_CURVE('E265',#52,#369,#403,.T.);
#405=ORIENTED_EDGE('',*,*,#404,.T.);
#406=EDGE_LOOP('',(#371,#372,#405));
#407=FACE_BOUND('',#406,.T.);
#408=ADVANCED_FACE('F182',(#407),#76,.T.);
#409=CARTESIAN_POINT('',(-15.,-8.66025403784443,-1.33974596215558));
#410=VERTEX_POINT('',#409);
#411=EDGE_CURVE('E170',#410,#52,#403,.T.);
#412=ORIENTED_EDGE('',*,*,#411,.T.);
#413=ORIENTED_EDGE('',*,*,#53,.F.);
#414=EDGE_CURVE('E135',#41,#410,#155,.F.);
#415=ORIENTED_EDGE('',*,*,#414,.T.);
#416=EDGE_LOOP('',(#412,#413,#415));
#417=FACE_BOUND('',#416,.T.);
#418=ADVANCED_FACE('F270',(#417),#76,.T.);
#419=CARTESIAN_POINT('',(15.,8.66025403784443,-16.));
#420=DIRECTION('',(0.499999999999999,0.866025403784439,0.));
#421=DIRECTION('',(-0.86602540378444,0.5,0.));
#422=AXIS2_PLACEMENT_3D('',#419,#420,#421);
#423=PLANE('',#422);
#424=CARTESIAN_POINT('',(-0.000200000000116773,17.3206235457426,-14.660187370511));
#425=CARTESIAN_POINT('',(0.32949410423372,17.130274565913,-14.770078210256));
#426=CARTESIAN_POINT('',(0.660474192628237,16.9391831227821,-14.8749824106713));
#427=CARTESIAN_POINT('',(1.32508844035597,16.5554679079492,-15.0734314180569));
#428=CARTESIAN_POINT('',(1.65872343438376,16.3628436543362,-15.1669724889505));
#429=CARTESIAN_POINT('',(2.32929228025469,15.9756905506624,-15.3414378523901));
#430=CARTESIAN_POINT('',(2.66623200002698,15.7811583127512,-15.4223322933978));
#431=CARTESIAN_POINT('',(3.34245276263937,15.3907420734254,-15.5697673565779));
#432=CARTESIAN_POINT('',(3.6817336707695,15.1948581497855,-15.6363087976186));
#433=CARTESIAN_POINT('',(4.35394314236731,14.8067578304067,-15.7522076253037));
#434=CARTESIAN_POINT('',(4.68682180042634,14.6145702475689,-15.8019486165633));
#435=CARTESIAN_POINT('',(5.3541044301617,14.2293144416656,-15.8853532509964));
#436=CARTESIAN_POINT('',(5.6885084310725,14.0362462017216,-15.9190165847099));
#437=CARTESIAN_POINT('',(6.35787818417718,13.6497853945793,-15.9694159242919));
#438=CARTESIAN_POINT('',(6.69284279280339,13.45639348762,-15.9861720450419));
#439=CARTESIAN_POINT('',(7.36308121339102,13.0694311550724,-16.002396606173));
#440=CARTESIAN_POINT('',(7.69835501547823,12.875860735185,-16.0018655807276));
#441=CARTESIAN_POINT('',(8.32514688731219,12.5139822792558,-15.9847233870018));
#442=CARTESIAN_POINT('',(8.61670962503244,12.3456484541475,-15.970203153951));
#443=CARTESIAN_POINT('',(9.19916443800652,12.0093680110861,-15.9283628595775));
#444=CARTESIAN_POINT('',(9.49005646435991,11.8414214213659,-15.9010418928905));
#445=CARTESIAN_POINT('',(10.0710118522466,11.5060066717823,-15.8340764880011));
#446=CARTESIAN_POINT('',(10.3610743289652,11.338539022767,-15.7944218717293));
#447=CARTESIAN_POINT('',(10.939839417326,11.0043888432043,-15.7034848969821));
#448=CARTESIAN_POINT('',(11.2285419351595,10.8377063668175,-15.6522017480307));
#449=CARTESIAN_POINT('',(12.1049144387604,10.3317324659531,-15.4796131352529));
#450=CARTESIAN_POINT('',(12.6900465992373,9.9939062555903,-15.3410988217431));
#451=CARTESIAN_POINT('',(13.8515859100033,9.32329122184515,-15.0267280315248));
#452=CARTESIAN_POINT('',(14.4280079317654,8.99049381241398,-14.8509453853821));
#453=CARTESIAN_POINT('',(15.0001999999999,8.66013856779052,-14.660187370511));
#454=B_SPLINE_CURVE_WITH_KNOTS('',3,(#424,#425,#426,#427,#428,#429,#430,#431,#432,#433,#434,
#435,#436,#437,#438,#439,#440,#441,#442,#443,#444,#445,#446,#447,#448,#449,#450,#451,#452,#453),
.UNSPECIFIED.,.F.,.F.,(4,2,2,2,2,2,2,2,2,2,2,2,2,2,4),(0.,1.18875411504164,2.37789802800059,
3.56980778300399,4.76164951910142,5.92407379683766,7.08652044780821,8.24758247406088,
9.40860862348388,10.4193068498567,11.4300765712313,12.4416826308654,13.4533574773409,
15.5211962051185,17.5849760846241),.UNSPECIFIED.);
#455=CARTESIAN_POINT('',(-2.22044604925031E-13,17.3205080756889,-14.6602540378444));
#456=VERTEX_POINT('',#455);
#457=CARTESIAN_POINT('',(7.49999999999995,12.9903810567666,-16.));
#458=VERTEX_POINT('',#457);
#459=EDGE_CURVE('E236',#456,#458,#454,.T.);
#460=ORIENTED_EDGE('',*,*,#459,.F.);
#461=DIRECTION('',(0.,0.,1.));
#462=VECTOR('',#461,1.);
#463=CARTESIAN_POINT('',(-1.11022302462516E-13,17.3205080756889,-16.));
#464=LINE('',#463,#462);
#465=EDGE_CURVE('E156',#456,#229,#464,.T.);
#466=ORIENTED_EDGE('',*,*,#465,.T.);
#467=ORIENTED_EDGE('',*,*,#230,.F.);
#468=ORIENTED_EDGE('',*,*,#321,.F.);
#469=DIRECTION('',(0.,0.,1.));
#470=VECTOR('',#469,1.);
#471=CARTESIAN_POINT('',(15.,8.66025403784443,-16.));
#472=LINE('',#471,#470);
#473=CARTESIAN_POINT('',(14.9999999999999,8.6602540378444,-14.6602540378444));
#474=VERTEX_POINT('',#473);
#475=EDGE_CURVE('E148',#474,#318,#472,.T.);
#476=ORIENTED_EDGE('',*,*,#475,.F.);
#477=EDGE_CURVE('E231',#458,#474,#454,.T.);
#478=ORIENTED_EDGE('',*,*,#477,.F.);
#479=EDGE_LOOP('',(#460,#466,#467,#468,#476,#478));
#480=FACE_BOUND('',#479,.T.);
#481=ADVANCED_FACE('F34',(#480),#423,.T.);
#482=CARTESIAN_POINT('',(14.9999999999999,-8.66025403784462,-16.));
#483=DIRECTION('',(1.,0.,0.));
#484=DIRECTION('',(0.,0.,-1.));
#485=AXIS2_PLACEMENT_3D('',#482,#483,#484);
#486=PLANE('',#485);
#487=CARTESIAN_POINT('',(15.0000000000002,-23.3393093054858,-8.64231244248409));
#488=CARTESIAN_POINT('',(15.,-23.0113763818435,-8.80158336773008));
#489=CARTESIAN_POINT('',(14.9999999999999,-22.6830606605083,-8.96006575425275));
#490=CARTESIAN_POINT('',(14.9999999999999,-22.0255837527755,-9.27527498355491));
#491=CARTESIAN_POINT('',(14.9999999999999,-21.6964225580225,-9.43200180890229));
#492=CARTESIAN_POINT('',(14.9999999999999,-20.707464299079,-9.89932208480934));
#493=CARTESIAN_POINT('',(14.9999999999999,-20.046288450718,-10.20700863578));
#494=CARTESIAN_POINT('',(14.9999999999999,-18.7159764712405,-10.8144230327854));
#495=CARTESIAN_POINT('',(14.9999999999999,-18.0468166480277,-11.1140991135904));
#496=CARTESIAN_POINT('',(14.9999999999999,-16.7032011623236,-11.7012916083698));
#497=CARTESIAN_POINT('',(14.9999999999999,-16.0287457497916,-11.988808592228));
#498=CARTESIAN_POINT('',(14.9999999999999,-14.6515945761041,-12.5574989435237));
#499=CARTESIAN_POINT('',(14.9999999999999,-13.9486896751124,-12.838168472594));
#500=CARTESIAN_POINT('',(14.9999999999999,-12.5346804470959,-13.378451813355));
#501=CARTESIAN_POINT('',(14.9999999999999,-11.8235752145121,-13.6380632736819));
#502=CARTESIAN_POINT('',(14.9999999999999,-10.3933623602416,-14.1294688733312));
#503=CARTESIAN_POINT('',(14.9999999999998,-9.6742739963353,-14.36131861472));
#504=CARTESIAN_POINT('',(15.,-8.22571576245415,-14.7898262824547));
#505=CARTESIAN_POINT('',(15.0000000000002,-7.49624921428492,-14.9864952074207));
#506=CARTESIAN_POINT('',(15.0000000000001,-6.3961027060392,-15.2475095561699));
#507=CARTESIAN_POINT('',(14.9999999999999,-6.02939002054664,-15.3286764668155));
#508=CARTESIAN_POINT('',(14.9999999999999,-5.29344467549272,-15.4787138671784));
#509=CARTESIAN_POINT('',(14.9999999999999,-4.92421206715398,-15.5475846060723));
#510=CARTESIAN_POINT('',(14.9999999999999,-4.18347621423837,-15.6718186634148));
#511=CARTESIAN_POINT('',(14.9999999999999,-3.81197300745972,-15.7271822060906));
#512=CARTESIAN_POINT('',(14.9999999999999,-3.06708460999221,-15.8233002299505));
#513=CARTESIAN_POINT('',(14.9999999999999,-2.69369950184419,-15.864055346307));
#514=CARTESIAN_POINT('',(14.9999999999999,-1.95047864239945,-15.929631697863));
#515=CARTESIAN_POINT('',(14.9999999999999,-1.58066088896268,-15.9546556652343));
#516=CARTESIAN_POINT('',(14.9999999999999,-0.840299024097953,-15.9890379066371));
#517=CARTESIAN_POINT('',(14.9999999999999,-0.46975492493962,-15.9983964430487));
#518=CARTESIAN_POINT('',(14.9999999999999,0.271400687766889,-16.0012249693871));
#519=CARTESIAN_POINT('',(14.9999999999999,0.642012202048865,-15.9946947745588));
#520=CARTESIAN_POINT('',(15.,1.38262798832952,-15.9659057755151));
#521=CARTESIAN_POINT('',(15.0000000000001,1.75263223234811,-15.9436462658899));
#522=CARTESIAN_POINT('',(15.0000000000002,2.6393716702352,-15.8719254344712));
#523=CARTESIAN_POINT('',(15.,3.1555250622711,-15.8151402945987));
#524=CARTESIAN_POINT('',(14.9999999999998,4.18405620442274,-15.6740334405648));
#525=CARTESIAN_POINT('',(14.9999999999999,4.69643344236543,-15.589708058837));
#526=CARTESIAN_POINT('',(14.9999999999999,5.71689756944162,-15.3965200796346));
#527=CARTESIAN_POINT('',(14.9999999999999,6.22498092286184,-15.2876389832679));
#528=CARTESIAN_POINT('',(14.9999999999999,7.23607939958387,-15.0486638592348));
#529=CARTESIAN_POINT('',(14.9999999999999,7.73909459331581,-14.9185701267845));
#530=CARTESIAN_POINT('',(14.9999999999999,8.75152378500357,-14.6371511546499));
#531=CARTESIAN_POINT('',(14.9999999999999,9.2608208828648,-14.4854082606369));
#532=CARTESIAN_POINT('',(14.9999999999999,10.2743970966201,-14.1660832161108));
#533=CARTESIAN_POINT('',(14.9999999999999,10.7786761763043,-13.9985009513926));
#534=CARTESIAN_POINT('',(14.9999999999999,11.7824677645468,-13.6501727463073));
#535=CARTESIAN_POINT('',(14.9999999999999,12.2819817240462,-13.4694309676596));
#536=CARTESIAN_POINT('',(14.9999999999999,13.2768545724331,-13.0969264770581));
#537=CARTESIAN_POINT('',(14.9999999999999,13.7722135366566,-12.9051639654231));
#538=CARTESIAN_POINT('',(14.9999999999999,15.043667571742,-12.3992939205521));
#539=CARTESIAN_POINT('',(14.9999999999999,15.8170452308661,-12.0783627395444));
#540=CARTESIAN_POINT('',(14.9999999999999,17.3564052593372,-11.4191722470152));
#541=CARTESIAN_POINT('',(14.9999999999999,18.1223869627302,-11.0809113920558));
#542=CARTESIAN_POINT('',(14.9999999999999,19.6485392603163,-10.3909410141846));
#543=CARTESIAN_POINT('',(14.9999999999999,20.4087079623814,-10.0392273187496));
#544=CARTESIAN_POINT('',(14.9999999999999,21.9240967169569,-9.32538900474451));
#545=CARTESIAN_POINT('',(14.9999999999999,22.6793169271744,-8.96326471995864));
#546=CARTESIAN_POINT('',(14.9999999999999,24.1867764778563,-8.23025205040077));
#547=CARTESIAN_POINT('',(14.9999999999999,24.9390102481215,-7.85935223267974));
#548=CARTESIAN_POINT('',(14.9999999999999,26.4401635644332,-7.11090353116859));
#549=CARTESIAN_POINT('',(14.9999999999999,27.1890830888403,-6.73335460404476));
#550=CARTESIAN_POINT('',(14.9999999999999,28.6840389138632,-5.972922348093));
#551=CARTESIAN_POINT('',(14.9999999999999,29.4300757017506,-5.59003997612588));
#552=CARTESIAN_POINT('',(14.9999999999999,30.9198465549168,-4.81983066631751));
#553=CARTESIAN_POINT('',(14.9999999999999,31.6635806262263,-4.43250374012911));
#554=CARTESIAN_POINT('',(14.9999999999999,33.7472761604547,-3.34077831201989));
#555=CARTESIAN_POINT('',(14.9999999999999,35.0850614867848,-2.63222696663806));
#556=CARTESIAN_POINT('',(14.9999999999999,37.7560146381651,-1.2063346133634));
#557=CARTESIAN_POINT('',(14.9999999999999,39.0891822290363,-0.488993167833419));
#558=CARTESIAN_POINT('',(14.9999999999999,41.7479806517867,0.950164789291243));
#559=CARTESIAN_POINT('',(14.9999999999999,43.0736221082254,1.6719616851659));
#560=CARTESIAN_POINT('',(14.9999999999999,45.0599534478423,2.75844249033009));
#561=CARTESIAN_POINT('',(14.9999999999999,45.7216867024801,3.12122149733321));
#562=CARTESIAN_POINT('',(14.9999999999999,47.0445303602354,3.8479113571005));
#563=CARTESIAN_POINT('',(14.9999999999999,47.7056407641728,4.21182220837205));
#564=CARTESIAN_POINT('',(15.,48.366476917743,4.57623052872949));
#565=B_SPLINE_CURVE_WITH_KNOTS('',3,(#487,#488,#489,#490,#491,#492,#493,#494,#495,#496,#497,
#498,#499,#500,#501,#502,#503,#504,#505,#506,#507,#508,#509,#510,#511,#512,#513,#514,#515,#516,
#517,#518,#519,#520,#521,#522,#523,#524,#525,#526,#527,#528,#529,#530,#531,#532,#533,#534,#535,
#536,#537,#538,#539,#540,#541,#542,#543,#544,#545,#546,#547,#548,#549,#550,#551,#552,#553,#554,
#555,#556,#557,#558,#559,#560,#561,#562,#563,#564),.UNSPECIFIED.,.F.,.F.,(4,2,2,2,2,2,2,2,2,2,2,
2,2,2,2,2,2,2,2,2,2,2,2,2,2,2,2,2,2,2,2,2,2,2,2,2,2,2,4),(0.,1.09369135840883,2.1873935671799,
4.37511793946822,6.57462034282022,8.77401954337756,11.0443689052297,13.3149714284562,
15.5809474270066,17.8462137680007,18.9728046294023,20.0993726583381,21.2259219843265,
22.3524223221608,23.4640902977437,24.5757396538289,25.6874019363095,26.7991140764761,
28.3560578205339,29.913208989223,31.4715371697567,33.0298436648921,34.6238022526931,
36.2177723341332,37.8112404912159,39.4046796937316,41.9163419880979,44.4282283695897,
46.9409002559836,49.4534916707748,51.9695595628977,54.4856438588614,57.001282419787,
59.5169143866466,64.058386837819,68.6000863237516,73.1282984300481,75.3922533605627,
77.6562053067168),.UNSPECIFIED.);
#566=CARTESIAN_POINT('',(14.9999999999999,-1.66533453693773E-13,-16.0000000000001));
#567=VERTEX_POINT('',#566);
#568=EDGE_CURVE('E225',#474,#567,#565,.F.);
#569=ORIENTED_EDGE('',*,*,#568,.F.);
#570=ORIENTED_EDGE('',*,*,#475,.T.);
#571=ORIENTED_EDGE('',*,*,#319,.F.);
#572=ORIENTED_EDGE('',*,*,#362,.F.);
#573=DIRECTION('',(0.,0.,1.));
#574=VECTOR('',#573,1.);
#575=CARTESIAN_POINT('',(14.9999999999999,-8.66025403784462,-16.));
#576=LINE('',#575,#574);
#577=CARTESIAN_POINT('',(14.9999999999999,-8.66025403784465,-14.6602540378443));
#578=VERTEX_POINT('',#577);
#579=EDGE_CURVE('E238',#578,#359,#576,.T.);
#580=ORIENTED_EDGE('',*,*,#579,.F.);
#581=EDGE_CURVE('E219',#567,#578,#565,.F.);
#582=ORIENTED_EDGE('',*,*,#581,.F.);
#583=EDGE_LOOP('',(#569,#570,#571,#572,#580,#582));
#584=FACE_BOUND('',#583,.T.);
#585=ADVANCED_FACE('F209',(#584),#486,.T.);
#586=CARTESIAN_POINT('',(14.9999999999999,-8.66025403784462,-16.));
#587=DIRECTION('',(0.5,-0.866025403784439,0.));
#588=DIRECTION('',(0.866025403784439,0.499999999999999,0.));
#589=AXIS2_PLACEMENT_3D('',#586,#587,#588);
#590=PLANE('',#589);
#591=CARTESIAN_POINT('',(15.0002,-8.66013856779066,-14.660187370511));
#592=CARTESIAN_POINT('',(14.6705058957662,-8.8504875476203,-14.770078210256));
#593=CARTESIAN_POINT('',(14.3395258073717,-9.04157899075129,-14.8749824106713));
#594=CARTESIAN_POINT('',(13.674911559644,-9.42529420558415,-15.0734314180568));
#595=CARTESIAN_POINT('',(13.3412765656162,-9.61791845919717,-15.1669724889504));
#596=CARTESIAN_POINT('',(12.6707077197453,-10.0050715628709,-15.3414378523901));
#597=CARTESIAN_POINT('',(12.333767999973,-10.1996038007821,-15.4223322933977));
#598=CARTESIAN_POINT('',(11.6575472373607,-10.590020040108,-15.5697673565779));
#599=CARTESIAN_POINT('',(11.3182663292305,-10.7859039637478,-15.6363087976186));
#600=CARTESIAN_POINT('',(10.6460568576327,-11.1740042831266,-15.7522076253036));
#601=CARTESIAN_POINT('',(10.3131781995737,-11.3661918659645,-15.8019486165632));
#602=CARTESIAN_POINT('',(9.64589556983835,-11.7514476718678,-15.8853532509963));
#603=CARTESIAN_POINT('',(9.31149156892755,-11.9445159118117,-15.9190165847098));
#604=CARTESIAN_POINT('',(8.6421218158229,-12.3309767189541,-15.9694159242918));
#605=CARTESIAN_POINT('',(8.30715720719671,-12.5243686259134,-15.9861720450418));
#606=CARTESIAN_POINT('',(7.63691878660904,-12.9113309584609,-16.0023966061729));
#607=CARTESIAN_POINT('',(7.30164498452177,-13.1049013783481,-16.0018655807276));
#608=CARTESIAN_POINT('',(6.67485311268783,-13.4667798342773,-15.9847233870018));
#609=CARTESIAN_POINT('',(6.38329037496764,-13.6351136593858,-15.9702031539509));
#610=CARTESIAN_POINT('',(5.80083556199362,-13.9713941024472,-15.9283628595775));
#611=CARTESIAN_POINT('',(5.50994353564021,-14.1393406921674,-15.9010418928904));
#612=CARTESIAN_POINT('',(4.92898814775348,-14.474755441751,-15.834076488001));
#613=CARTESIAN_POINT('',(4.63892567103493,-14.6422230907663,-15.7944218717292));
#614=CARTESIAN_POINT('',(4.06016058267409,-14.976373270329,-15.703484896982));
#615=CARTESIAN_POINT('',(3.7714580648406,-15.1430557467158,-15.6522017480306));
#616=CARTESIAN_POINT('',(2.89508556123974,-15.6490296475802,-15.4796131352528));
#617=CARTESIAN_POINT('',(2.3099534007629,-15.986855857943,-15.341098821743));
#618=CARTESIAN_POINT('',(1.1484140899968,-16.6574708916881,-15.0267280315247));
#619=CARTESIAN_POINT('',(0.571992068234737,-16.9902683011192,-14.8509453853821));
#620=CARTESIAN_POINT('',(-0.000199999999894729,-17.3206235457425,-14.6601873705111));
#621=B_SPLINE_CURVE_WITH_KNOTS('',3,(#591,#592,#593,#594,#595,#596,#597,#598,#599,#600,#601,
#602,#603,#604,#605,#606,#607,#608,#609,#610,#611,#612,#613,#614,#615,#616,#617,#618,#619,#620),
.UNSPECIFIED.,.F.,.F.,(4,2,2,2,2,2,2,2,2,2,2,2,2,2,4),(0.,1.18875411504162,2.37789802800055,
3.56980778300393,4.76164951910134,5.92407379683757,7.08652044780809,8.24758247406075,
9.40860862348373,10.4193068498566,11.4300765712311,12.4416826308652,13.4533574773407,
15.5211962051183,17.5849760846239),.UNSPECIFIED.);
#622=CARTESIAN_POINT('',(7.49999999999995,-12.9903810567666,-16.));
#623=VERTEX_POINT('',#622);
#624=EDGE_CURVE('E56',#578,#623,#621,.T.);
#625=ORIENTED_EDGE('',*,*,#624,.F.);
#626=ORIENTED_EDGE('',*,*,#579,.T.);
#627=ORIENTED_EDGE('',*,*,#360,.F.);
#628=ORIENTED_EDGE('',*,*,#370,.F.);
#629=DIRECTION('',(0.,0.,1.));
#630=VECTOR('',#629,1.);
#631=CARTESIAN_POINT('',(0.,-17.3205080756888,-16.0000000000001));
#632=LINE('',#631,#630);
#633=CARTESIAN_POINT('',(1.11022302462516E-13,-17.3205080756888,-14.6602540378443));
#634=VERTEX_POINT('',#633);
#635=EDGE_CURVE('E241',#634,#369,#632,.T.);
#636=ORIENTED_EDGE('',*,*,#635,.F.);
#637=EDGE_CURVE('E226',#623,#634,#621,.T.);
#638=ORIENTED_EDGE('',*,*,#637,.F.);
#639=EDGE_LOOP('',(#625,#626,#627,#628,#636,#638));
#640=FACE_BOUND('',#639,.T.);
#641=ADVANCED_FACE('F213',(#640),#590,.T.);
#642=CARTESIAN_POINT('',(-15.,-8.66025403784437,-16.));
#643=DIRECTION('',(-0.499999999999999,-0.866025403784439,0.));
#644=DIRECTION('',(0.86602540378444,-0.5,0.));
#645=AXIS2_PLACEMENT_3D('',#642,#643,#644);
#646=PLANE('',#645);
#647=CARTESIAN_POINT('',(0.000200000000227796,-17.3206235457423,-14.660187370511));
#648=CARTESIAN_POINT('',(-0.329494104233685,-17.1302745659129,-14.770078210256));
#649=CARTESIAN_POINT('',(-0.660474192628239,-16.939183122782,-14.8749824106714));
#650=CARTESIAN_POINT('',(-1.32508844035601,-16.5554679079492,-15.0734314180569));
#651=CARTESIAN_POINT('',(-1.6587234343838,-16.3628436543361,-15.1669724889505));
#652=CARTESIAN_POINT('',(-2.32929228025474,-15.9756905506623,-15.3414378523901));
#653=CARTESIAN_POINT('',(-2.66623200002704,-15.7811583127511,-15.4223322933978));
#654=CARTESIAN_POINT('',(-3.34245276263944,-15.3907420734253,-15.569767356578));
#655=CARTESIAN_POINT('',(-3.68173367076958,-15.1948581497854,-15.6363087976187));
#656=CARTESIAN_POINT('',(-4.35394314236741,-14.8067578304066,-15.7522076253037));
#657=CARTESIAN_POINT('',(-4.68682180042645,-14.6145702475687,-15.8019486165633));
#658=CARTESIAN_POINT('',(-5.35410443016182,-14.2293144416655,-15.8853532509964));
#659=CARTESIAN_POINT('',(-5.68850843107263,-14.0362462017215,-15.9190165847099));
#660=CARTESIAN_POINT('',(-6.35787818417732,-13.6497853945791,-15.9694159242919));
#661=CARTESIAN_POINT('',(-6.69284279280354,-13.4563934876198,-15.9861720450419));
#662=CARTESIAN_POINT('',(-7.3630812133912,-13.0694311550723,-16.002396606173));
#663=CARTESIAN_POINT('',(-7.69835501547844,-12.8758607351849,-16.0018655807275));
#664=CARTESIAN_POINT('',(-8.32514688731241,-12.5139822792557,-15.9847233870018));
#665=CARTESIAN_POINT('',(-8.61670962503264,-12.3456484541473,-15.9702031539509));
#666=CARTESIAN_POINT('',(-9.19916443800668,-12.009368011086,-15.9283628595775));
#667=CARTESIAN_POINT('',(-9.49005646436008,-11.8414214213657,-15.9010418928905));
#668=CARTESIAN_POINT('',(-10.0710118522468,-11.5060066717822,-15.834076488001));
#669=CARTESIAN_POINT('',(-10.3610743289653,-11.3385390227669,-15.7944218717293));
#670=CARTESIAN_POINT('',(-10.9398394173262,-11.0043888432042,-15.703484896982));
#671=CARTESIAN_POINT('',(-11.2285419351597,-10.8377063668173,-15.6522017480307));
#672=CARTESIAN_POINT('',(-12.1049144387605,-10.331732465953,-15.4796131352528));
#673=CARTESIAN_POINT('',(-12.6900465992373,-9.99390625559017,-15.341098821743));
#674=CARTESIAN_POINT('',(-13.8515859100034,-9.32329122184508,-15.0267280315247));
#675=CARTESIAN_POINT('',(-14.4280079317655,-8.99049381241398,-14.8509453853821));
#676=CARTESIAN_POINT('',(-15.0002000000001,-8.66013856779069,-14.660187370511));
#677=B_SPLINE_CURVE_WITH_KNOTS('',3,(#647,#648,#649,#650,#651,#652,#653,#654,#655,#656,#657,
#658,#659,#660,#661,#662,#663,#664,#665,#666,#667,#668,#669,#670,#671,#672,#673,#674,#675,#676),
.UNSPECIFIED.,.F.,.F.,(4,2,2,2,2,2,2,2,2,2,2,2,2,2,4),(0.,1.18875411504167,2.37789802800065,
3.56980778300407,4.76164951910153,5.9240737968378,7.08652044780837,8.24758247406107,
9.4086086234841,10.4193068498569,11.4300765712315,12.4416826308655,13.453357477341,
15.5211962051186,17.5849760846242),.UNSPECIFIED.);
#678=CARTESIAN_POINT('',(-7.49999999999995,-12.9903810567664,-16.));
#679=VERTEX_POINT('',#678);
#680=EDGE_CURVE('E49',#634,#679,#677,.T.);
#681=ORIENTED_EDGE('',*,*,#680,.F.);
#682=ORIENTED_EDGE('',*,*,#635,.T.);
#683=ORIENTED_EDGE('',*,*,#404,.F.);
#684=ORIENTED_EDGE('',*,*,#411,.F.);
#685=DIRECTION('',(0.,0.,1.));
#686=VECTOR('',#685,1.);
#687=CARTESIAN_POINT('',(-15.,-8.66025403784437,-16.));
#688=LINE('',#687,#686);
#689=CARTESIAN_POINT('',(-15.,-8.66025403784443,-14.6602540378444));
#690=VERTEX_POINT('',#689);
#691=EDGE_CURVE('E244',#690,#410,#688,.T.);
#692=ORIENTED_EDGE('',*,*,#691,.F.);
#693=EDGE_CURVE('E285',#679,#690,#677,.T.);
#694=ORIENTED_EDGE('',*,*,#693,.F.);
#695=EDGE_LOOP('',(#681,#682,#683,#684,#692,#694));
#696=FACE_BOUND('',#695,.T.);
#697=ADVANCED_FACE('F275',(#696),#646,.T.);
#698=CARTESIAN_POINT('',(-15.,-8.66025403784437,-16.));
#699=DIRECTION('',(-1.,0.,0.));
#700=DIRECTION('',(0.,0.,1.));
#701=AXIS2_PLACEMENT_3D('',#698,#699,#700);
#702=PLANE('',#701);
#703=CARTESIAN_POINT('',(-15.0000000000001,-23.3393093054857,-8.64231244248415));
#704=CARTESIAN_POINT('',(-15.0000000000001,-23.0113763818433,-8.8015833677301));
#705=CARTESIAN_POINT('',(-15.,-22.6830606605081,-8.96006575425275));
#706=CARTESIAN_POINT('',(-15.,-22.0255837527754,-9.27527498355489));
#707=CARTESIAN_POINT('',(-15.,-21.6964225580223,-9.43200180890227));
#708=CARTESIAN_POINT('',(-15.,-20.7074642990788,-9.89932208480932));
#709=CARTESIAN_POINT('',(-15.,-20.0462884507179,-10.20700863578));
#710=CARTESIAN_POINT('',(-15.,-18.7159764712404,-10.8144230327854));
#711=CARTESIAN_POINT('',(-15.,-18.0468166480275,-11.1140991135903));
#712=CARTESIAN_POINT('',(-15.,-16.7032011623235,-11.7012916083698));
#713=CARTESIAN_POINT('',(-15.,-16.0287457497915,-11.9888085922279));
#714=CARTESIAN_POINT('',(-15.,-14.651594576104,-12.5574989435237));
#715=CARTESIAN_POINT('',(-15.,-13.9486896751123,-12.8381684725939));
#716=CARTESIAN_POINT('',(-15.,-12.5346804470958,-13.378451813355));
#717=CARTESIAN_POINT('',(-15.0000000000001,-11.823575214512,-13.6380632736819));
#718=CARTESIAN_POINT('',(-15.,-10.3933623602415,-14.1294688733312));
#719=CARTESIAN_POINT('',(-14.9999999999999,-9.67427399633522,-14.3613186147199));
#720=CARTESIAN_POINT('',(-15.0000000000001,-8.22571576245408,-14.7898262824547));
#721=CARTESIAN_POINT('',(-15.0000000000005,-7.49624921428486,-14.9864952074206));
#722=CARTESIAN_POINT('',(-15.0000000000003,-6.39610270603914,-15.2475095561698));
#723=CARTESIAN_POINT('',(-15.0000000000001,-6.02939002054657,-15.3286764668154));
#724=CARTESIAN_POINT('',(-14.9999999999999,-5.29344467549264,-15.4787138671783));
#725=CARTESIAN_POINT('',(-15.,-4.92421206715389,-15.5475846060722));
#726=CARTESIAN_POINT('',(-15.,-4.18347621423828,-15.6718186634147));
#727=CARTESIAN_POINT('',(-15.,-3.81197300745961,-15.7271822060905));
#728=CARTESIAN_POINT('',(-15.,-3.06708460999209,-15.8233002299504));
#729=CARTESIAN_POINT('',(-15.,-2.69369950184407,-15.8640553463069));
#730=CARTESIAN_POINT('',(-15.,-1.95047864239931,-15.9296316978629));
#731=CARTESIAN_POINT('',(-15.,-1.58066088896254,-15.9546556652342));
#732=CARTESIAN_POINT('',(-15.,-0.840299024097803,-15.989037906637));
#733=CARTESIAN_POINT('',(-15.,-0.469754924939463,-15.9983964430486));
#734=CARTESIAN_POINT('',(-15.,0.271400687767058,-16.0012249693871));
#735=CARTESIAN_POINT('',(-15.,0.642012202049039,-15.9946947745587));
#736=CARTESIAN_POINT('',(-15.,1.38262798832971,-15.965905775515));
#737=CARTESIAN_POINT('',(-15.,1.7526322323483,-15.9436462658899));
#738=CARTESIAN_POINT('',(-15.,2.63937167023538,-15.8719254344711));
#739=CARTESIAN_POINT('',(-15.,3.15552506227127,-15.8151402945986));
#740=CARTESIAN_POINT('',(-15.,4.18405620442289,-15.6740334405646));
#741=CARTESIAN_POINT('',(-15.,4.69643344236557,-15.5897080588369));
#742=CARTESIAN_POINT('',(-15.,5.71689756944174,-15.3965200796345));
#743=CARTESIAN_POINT('',(-15.,6.22498092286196,-15.2876389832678));
#744=CARTESIAN_POINT('',(-15.,7.23607939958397,-15.0486638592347));
#745=CARTESIAN_POINT('',(-15.,7.73909459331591,-14.9185701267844));
#746=CARTESIAN_POINT('',(-15.,8.75152378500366,-14.6371511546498));
#747=CARTESIAN_POINT('',(-15.,9.26082088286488,-14.4854082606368));
#748=CARTESIAN_POINT('',(-15.,10.2743970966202,-14.1660832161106));
#749=CARTESIAN_POINT('',(-15.,10.7786761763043,-13.9985009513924));
#750=CARTESIAN_POINT('',(-15.,11.7824677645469,-13.6501727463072));
#751=CARTESIAN_POINT('',(-15.,12.2819817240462,-13.4694309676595));
#752=CARTESIAN_POINT('',(-15.,13.2768545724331,-13.096926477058));
#753=CARTESIAN_POINT('',(-15.0000000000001,13.7722135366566,-12.905163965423));
#754=CARTESIAN_POINT('',(-15.0000000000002,15.043667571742,-12.399293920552));
#755=CARTESIAN_POINT('',(-15.,15.8170452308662,-12.0783627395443));
#756=CARTESIAN_POINT('',(-15.,17.3564052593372,-11.4191722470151));
#757=CARTESIAN_POINT('',(-15.,18.1223869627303,-11.0809113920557));
#758=CARTESIAN_POINT('',(-15.,19.6485392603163,-10.3909410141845));
#759=CARTESIAN_POINT('',(-15.,20.4087079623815,-10.0392273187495));
#760=CARTESIAN_POINT('',(-15.,21.9240967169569,-9.32538900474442));
#761=CARTESIAN_POINT('',(-15.,22.6793169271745,-8.96326471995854));
#762=CARTESIAN_POINT('',(-15.,24.1867764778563,-8.23025205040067));
#763=CARTESIAN_POINT('',(-15.,24.9390102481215,-7.85935223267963));
#764=CARTESIAN_POINT('',(-15.,26.4401635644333,-7.11090353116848));
#765=CARTESIAN_POINT('',(-15.,27.1890830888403,-6.73335460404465));
#766=CARTESIAN_POINT('',(-15.,28.6840389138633,-5.97292234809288));
#767=CARTESIAN_POINT('',(-15.,29.4300757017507,-5.59003997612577));
#768=CARTESIAN_POINT('',(-15.,30.9198465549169,-4.81983066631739));
#769=CARTESIAN_POINT('',(-15.,31.6635806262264,-4.43250374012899));
#770=CARTESIAN_POINT('',(-15.,33.7472761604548,-3.34077831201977));
#771=CARTESIAN_POINT('',(-15.,35.0850614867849,-2.63222696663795));
#772=CARTESIAN_POINT('',(-15.,37.7560146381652,-1.20633461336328));
#773=CARTESIAN_POINT('',(-15.,39.0891822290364,-0.488993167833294));
#774=CARTESIAN_POINT('',(-15.,41.7479806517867,0.950164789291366));
#775=CARTESIAN_POINT('',(-15.,43.0736221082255,1.67196168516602));
#776=CARTESIAN_POINT('',(-15.,45.0599534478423,2.75844249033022));
#777=CARTESIAN_POINT('',(-15.,45.7216867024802,3.12122149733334));
#778=CARTESIAN_POINT('',(-15.,47.0445303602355,3.84791135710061));
#779=CARTESIAN_POINT('',(-15.,47.7056407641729,4.21182220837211));
#780=CARTESIAN_POINT('',(-15.,48.3664769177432,4.57623052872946));
#781=B_SPLINE_CURVE_WITH_KNOTS('',3,(#703,#704,#705,#706,#707,#708,#709,#710,#711,#712,#713,
#714,#715,#716,#717,#718,#719,#720,#721,#722,#723,#724,#725,#726,#727,#728,#729,#730,#731,#732,
#733,#734,#735,#736,#737,#738,#739,#740,#741,#742,#743,#744,#745,#746,#747,#748,#749,#750,#751,
#752,#753,#754,#755,#756,#757,#758,#759,#760,#761,#762,#763,#764,#765,#766,#767,#768,#769,#770,
#771,#772,#773,#774,#775,#776,#777,#778,#779,#780),.UNSPECIFIED.,.F.,.F.,(4,2,2,2,2,2,2,2,2,2,2,
2,2,2,2,2,2,2,2,2,2,2,2,2,2,2,2,2,2,2,2,2,2,2,2,2,2,2,4),(0.,1.09369135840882,2.18739356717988,
4.37511793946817,6.57462034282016,8.77401954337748,11.0443689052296,13.3149714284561,
15.5809474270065,17.8462137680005,18.9728046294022,20.099372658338,21.2259219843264,
22.3524223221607,23.4640902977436,24.5757396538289,25.6874019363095,26.7991140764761,
28.3560578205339,29.9132089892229,31.4715371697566,33.029843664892,34.623802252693,
36.2177723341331,37.8112404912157,39.4046796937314,41.9163419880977,44.4282283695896,
46.9409002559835,49.4534916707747,51.9695595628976,54.4856438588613,57.0012824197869,
59.5169143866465,64.0583868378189,68.6000863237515,73.128298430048,75.3922533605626,
77.6562053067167),.UNSPECIFIED.);
#782=CARTESIAN_POINT('',(-15.,1.38777878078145E-13,-16.));
#783=VERTEX_POINT('',#782);
#784=EDGE_CURVE('E280',#690,#783,#781,.T.);
#785=ORIENTED_EDGE('',*,*,#784,.F.);
#786=ORIENTED_EDGE('',*,*,#691,.T.);
#787=ORIENTED_EDGE('',*,*,#414,.F.);
#788=ORIENTED_EDGE('',*,*,#158,.F.);
#789=DIRECTION('',(0.,0.,1.));
#790=VECTOR('',#789,1.);
#791=CARTESIAN_POINT('',(-15.0000000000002,8.66025403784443,-16.));
#792=LINE('',#791,#790);
#793=CARTESIAN_POINT('',(-15.0000000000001,8.66025403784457,-14.6602540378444));
#794=VERTEX_POINT('',#793);
#795=EDGE_CURVE('E247',#794,#157,#792,.T.);
#796=ORIENTED_EDGE('',*,*,#795,.F.);
#797=EDGE_CURVE('E282',#783,#794,#781,.T.);
#798=ORIENTED_EDGE('',*,*,#797,.F.);
#799=EDGE_LOOP('',(#785,#786,#787,#788,#796,#798));
#800=FACE_BOUND('',#799,.T.);
#801=ADVANCED_FACE('F278',(#800),#702,.T.);
#802=CARTESIAN_POINT('',(-15.0000000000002,8.66025403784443,-16.));
#803=DIRECTION('',(-0.5,0.866025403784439,0.));
#804=DIRECTION('',(-0.866025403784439,-0.499999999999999,0.));
#805=AXIS2_PLACEMENT_3D('',#802,#803,#804);
#806=PLANE('',#805);
#807=CARTESIAN_POINT('',(-15.0002000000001,8.66013856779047,-14.6601873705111));
#808=CARTESIAN_POINT('',(-14.6705058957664,8.85048754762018,-14.770078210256));
#809=CARTESIAN_POINT('',(-14.3395258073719,9.0415789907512,-14.8749824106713));
#810=CARTESIAN_POINT('',(-13.6749115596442,9.42529420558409,-15.0734314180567));
#811=CARTESIAN_POINT('',(-13.3412765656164,9.61791845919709,-15.1669724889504));
#812=CARTESIAN_POINT('',(-12.6707077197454,10.0050715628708,-15.34143785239));
#813=CARTESIAN_POINT('',(-12.3337679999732,10.1996038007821,-15.4223322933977));
#814=CARTESIAN_POINT('',(-11.6575472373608,10.5900200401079,-15.5697673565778));
#815=CARTESIAN_POINT('',(-11.3182663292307,10.7859039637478,-15.6363087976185));
#816=CARTESIAN_POINT('',(-10.6460568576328,11.1740042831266,-15.7522076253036));
#817=CARTESIAN_POINT('',(-10.3131781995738,11.3661918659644,-15.8019486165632));
#818=CARTESIAN_POINT('',(-9.64589556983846,11.7514476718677,-15.8853532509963));
#819=CARTESIAN_POINT('',(-9.31149156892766,11.9445159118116,-15.9190165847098));
#820=CARTESIAN_POINT('',(-8.642121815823,12.330976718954,-15.9694159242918));
#821=CARTESIAN_POINT('',(-8.3071572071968,12.5243686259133,-15.9861720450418));
#822=CARTESIAN_POINT('',(-7.63691878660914,12.9113309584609,-16.0023966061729));
#823=CARTESIAN_POINT('',(-7.30164498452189,13.1049013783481,-16.0018655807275));
#824=CARTESIAN_POINT('',(-6.67485311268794,13.4667798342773,-15.9847233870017));
#825=CARTESIAN_POINT('',(-6.38329037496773,13.6351136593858,-15.9702031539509));
#826=CARTESIAN_POINT('',(-5.80083556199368,13.9713941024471,-15.9283628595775));
#827=CARTESIAN_POINT('',(-5.50994353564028,14.1393406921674,-15.9010418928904));
#828=CARTESIAN_POINT('',(-4.92898814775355,14.474755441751,-15.834076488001));
#829=CARTESIAN_POINT('',(-4.63892567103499,14.6422230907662,-15.7944218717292));
#830=CARTESIAN_POINT('',(-4.06016058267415,14.9763732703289,-15.703484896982));
#831=CARTESIAN_POINT('',(-3.77145806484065,15.1430557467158,-15.6522017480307));
#832=CARTESIAN_POINT('',(-2.89508556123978,15.6490296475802,-15.4796131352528));
#833=CARTESIAN_POINT('',(-2.30995340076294,15.986855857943,-15.341098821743));
#834=CARTESIAN_POINT('',(-1.14841408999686,16.6574708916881,-15.0267280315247));
#835=CARTESIAN_POINT('',(-0.571992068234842,16.9902683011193,-14.8509453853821));
#836=CARTESIAN_POINT('',(0.000199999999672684,17.3206235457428,-14.6601873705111));
#837=B_SPLINE_CURVE_WITH_KNOTS('',3,(#807,#808,#809,#810,#811,#812,#813,#814,#815,#816,#817,
#818,#819,#820,#821,#822,#823,#824,#825,#826,#827,#828,#829,#830,#831,#832,#833,#834,#835,#836),
.UNSPECIFIED.,.F.,.F.,(4,2,2,2,2,2,2,2,2,2,2,2,2,2,4),(0.,1.18875411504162,2.37789802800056,
3.56980778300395,4.76164951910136,5.9240737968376,7.08652044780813,8.24758247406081,
9.4086086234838,10.4193068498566,11.4300765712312,12.4416826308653,13.4533574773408,
15.5211962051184,17.584976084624),.UNSPECIFIED.);
#838=CARTESIAN_POINT('',(-7.50000000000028,12.9903810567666,-16.0000000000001));
#839=VERTEX_POINT('',#838);
#840=EDGE_CURVE('E287',#794,#839,#837,.T.);
#841=ORIENTED_EDGE('',*,*,#840,.F.);
#842=ORIENTED_EDGE('',*,*,#795,.T.);
#843=ORIENTED_EDGE('',*,*,#192,.F.);
#844=ORIENTED_EDGE('',*,*,#232,.F.);
#845=ORIENTED_EDGE('',*,*,#465,.F.);
#846=EDGE_CURVE('E266',#839,#456,#837,.T.);
#847=ORIENTED_EDGE('',*,*,#846,.F.);
#848=EDGE_LOOP('',(#841,#842,#843,#844,#845,#847));
#849=FACE_BOUND('',#848,.T.);
#850=ADVANCED_FACE('F299',(#849),#806,.T.);
#851=CARTESIAN_POINT('',(0.,0.,-7.99999999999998));
#852=DIRECTION('',(0.,0.,1.));
#853=DIRECTION('',(1.,0.,0.));
#854=AXIS2_PLACEMENT_3D('',#851,#852,#853);
#855=CONICAL_SURFACE('',#854,28.8564064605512,1.0471975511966);
#856=ORIENTED_EDGE('',*,*,#797,.T.);
#857=ORIENTED_EDGE('',*,*,#840,.T.);
#858=CARTESIAN_POINT('',(0.,0.,-16.));
#859=DIRECTION('',(0.,0.,-1.));
#860=DIRECTION('',(-1.,0.,0.));
#861=AXIS2_PLACEMENT_3D('',#858,#859,#860);
#862=CIRCLE('',#861,15.);
#863=EDGE_CURVE('E324',#783,#839,#862,.T.);
#864=ORIENTED_EDGE('',*,*,#863,.F.);
#865=EDGE_LOOP('',(#856,#857,#864));
#866=FACE_BOUND('',#865,.T.);
#867=ADVANCED_FACE('F184',(#866),#855,.T.);
#868=ORIENTED_EDGE('',*,*,#459,.T.);
#869=CARTESIAN_POINT('',(0.,0.,-16.));
#870=DIRECTION('',(0.,0.,-1.));
#871=DIRECTION('',(-1.,0.,0.));
#872=AXIS2_PLACEMENT_3D('',#869,#870,#871);
#873=CIRCLE('',#872,15.);
#874=EDGE_CURVE('E42',#458,#839,#873,.F.);
#875=ORIENTED_EDGE('',*,*,#874,.T.);
#876=ORIENTED_EDGE('',*,*,#846,.T.);
#877=EDGE_LOOP('',(#868,#875,#876));
#878=FACE_BOUND('',#877,.T.);
#879=ADVANCED_FACE('F309',(#878),#855,.T.);
#880=ORIENTED_EDGE('',*,*,#477,.T.);
#881=ORIENTED_EDGE('',*,*,#568,.T.);
#882=EDGE_CURVE('E254',#567,#458,#873,.F.);
#883=ORIENTED_EDGE('',*,*,#882,.T.);
#884=EDGE_LOOP('',(#880,#881,#883));
#885=FACE_BOUND('',#884,.T.);
#886=ADVANCED_FACE('F336',(#885),#855,.T.);
#887=ORIENTED_EDGE('',*,*,#581,.T.);
#888=ORIENTED_EDGE('',*,*,#624,.T.);
#889=EDGE_CURVE('E341',#623,#567,#873,.F.);
#890=ORIENTED_EDGE('',*,*,#889,.T.);
#891=EDGE_LOOP('',(#887,#888,#890));
#892=FACE_BOUND('',#891,.T.);
#893=ADVANCED_FACE('F339',(#892),#855,.T.);
#894=ORIENTED_EDGE('',*,*,#637,.T.);
#895=ORIENTED_EDGE('',*,*,#680,.T.);
#896=EDGE_CURVE('E41',#679,#623,#873,.F.);
#897=ORIENTED_EDGE('',*,*,#896,.T.);
#898=EDGE_LOOP('',(#894,#895,#897));
#899=FACE_BOUND('',#898,.T.);
#900=ADVANCED_FACE('F343',(#899),#855,.T.);
#901=ORIENTED_EDGE('',*,*,#693,.T.);
#902=ORIENTED_EDGE('',*,*,#784,.T.);
#903=EDGE_CURVE('E11',#783,#679,#873,.F.);
#904=ORIENTED_EDGE('',*,*,#903,.T.);
#905=EDGE_LOOP('',(#901,#902,#904));
#906=FACE_BOUND('',#905,.T.);
#907=ADVANCED_FACE('F311',(#906),#855,.T.);
#908=CARTESIAN_POINT('',(-15.0000000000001,25.9807621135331,-16.));
#909=DIRECTION('',(0.,0.,-1.));
#910=DIRECTION('',(-1.,0.,0.));
#911=AXIS2_PLACEMENT_3D('',#908,#909,#910);
#912=PLANE('',#911);
#913=CARTESIAN_POINT('',(0.,0.,-16.));
#914=DIRECTION('',(0.,0.,1.));
#915=DIRECTION('',(1.,0.,0.));
#916=AXIS2_PLACEMENT_3D('',#913,#914,#915);
#917=CIRCLE('',#916,10.);
#918=CARTESIAN_POINT('',(10.,0.,-16.));
#919=VERTEX_POINT('',#918);
#920=EDGE_CURVE('E321',#919,#919,#917,.T.);
#921=ORIENTED_EDGE('',*,*,#920,.T.);
#922=EDGE_LOOP('',(#921));
#923=FACE_BOUND('',#922,.T.);
#924=ORIENTED_EDGE('',*,*,#903,.F.);
#925=ORIENTED_EDGE('',*,*,#863,.T.);
#926=ORIENTED_EDGE('',*,*,#874,.F.);
#927=ORIENTED_EDGE('',*,*,#882,.F.);
#928=ORIENTED_EDGE('',*,*,#889,.F.);
#929=ORIENTED_EDGE('',*,*,#896,.F.);
#930=EDGE_LOOP('',(#924,#925,#926,#927,#928,#929));
#931=FACE_BOUND('',#930,.T.);
#932=ADVANCED_FACE('F215',(#923,#931),#912,.T.);
#933=CARTESIAN_POINT('',(0.,0.,-16.));
#934=DIRECTION('',(0.,0.,1.));
#935=DIRECTION('',(1.,0.,0.));
#936=AXIS2_PLACEMENT_3D('',#933,#934,#935);
#937=CYLINDRICAL_SURFACE('',#936,10.);
#938=ORIENTED_EDGE('',*,*,#920,.F.);
#939=EDGE_LOOP('',(#938));
#940=FACE_BOUND('',#939,.T.);
#941=ORIENTED_EDGE('',*,*,#31,.T.);
#942=EDGE_LOOP('',(#941));
#943=FACE_BOUND('',#942,.T.);
#944=ADVANCED_FACE('F183',(#940,#943),#937,.F.);
#945=CLOSED_SHELL('',(#71,#196,#237,#326,#367,#408,#418,#481,#585,#641,#697,#801,#850,#867,#879,
#886,#893,#900,#907,#932,#944));
#946=MANIFOLD_SOLID_BREP('B2',#945);
#947=ADVANCED_BREP_SHAPE_REPRESENTATION('',(#18,#946),#14);
#948=SHAPE_DEFINITION_REPRESENTATION(#9,#947);
ENDSEC;
END-ISO-10303-21;
